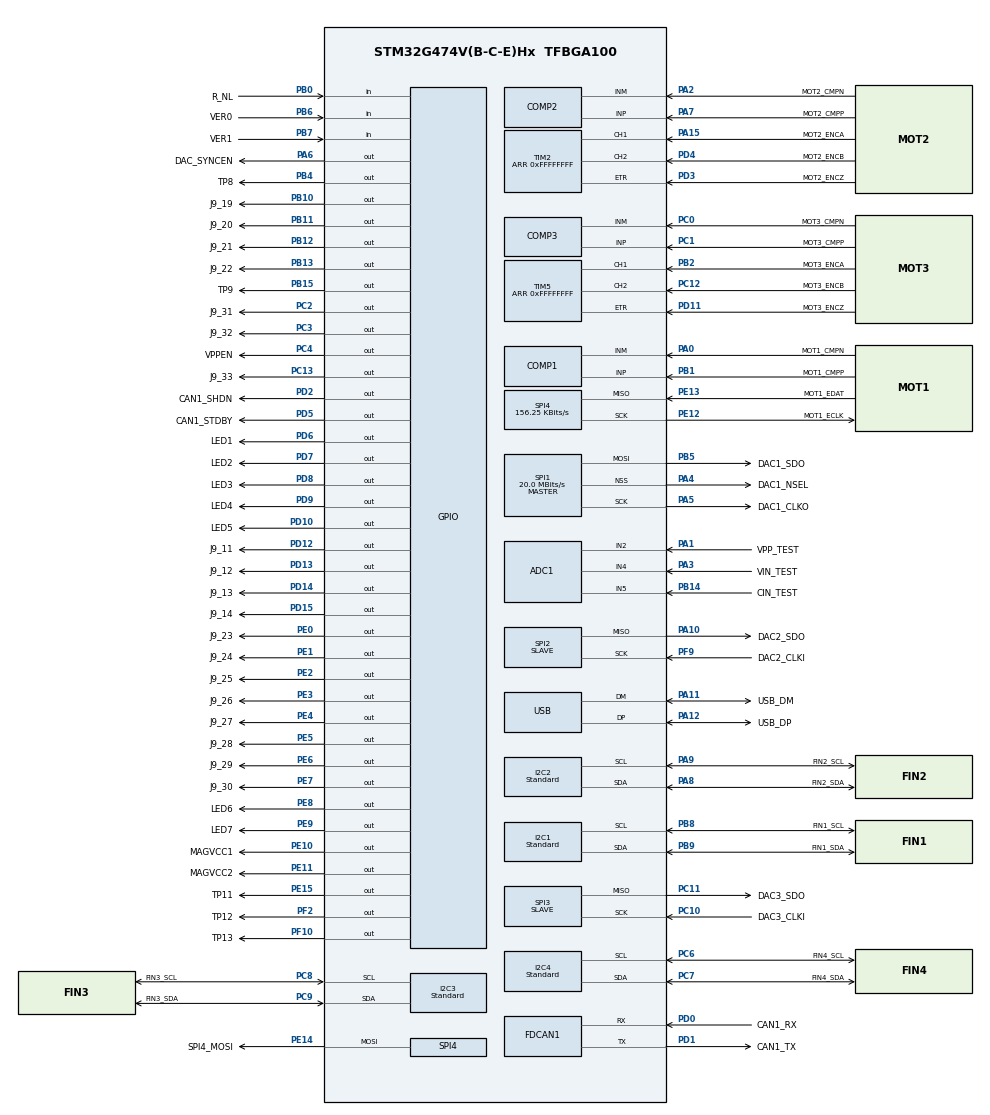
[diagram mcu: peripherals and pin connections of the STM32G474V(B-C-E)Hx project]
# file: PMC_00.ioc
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ADC1.Channel-1\#ChannelRegularConversion=ADC_CHANNEL_2
ADC1.Channel-10\#ChannelRegularConversion=ADC_CHANNEL_VBAT
ADC1.Channel-11\#ChannelRegularConversion=ADC_CHANNEL_VREFINT
ADC1.Channel-12\#ChannelRegularConversion=ADC_CHANNEL_VREFINT
ADC1.Channel-2\#ChannelRegularConversion=ADC_CHANNEL_2
ADC1.Channel-3\#ChannelRegularConversion=ADC_CHANNEL_4
ADC1.Channel-4\#ChannelRegularConversion=ADC_CHANNEL_4
ADC1.Channel-5\#ChannelRegularConversion=ADC_CHANNEL_5
ADC1.Channel-6\#ChannelRegularConversion=ADC_CHANNEL_5
ADC1.Channel-7\#ChannelRegularConversion=ADC_CHANNEL_TEMPSENSOR_ADC1
ADC1.Channel-8\#ChannelRegularConversion=ADC_CHANNEL_TEMPSENSOR_ADC1
ADC1.Channel-9\#ChannelRegularConversion=ADC_CHANNEL_VBAT
ADC1.ContinuousConvMode=DISABLE
ADC1.DMAContinuousRequests=ENABLE
ADC1.DiscontinuousConvMode=ENABLE
ADC1.EOCSelection=ADC_EOC_SEQ_CONV
ADC1.ExternalTrigConv=ADC_EXTERNALTRIG_T7_TRGO
ADC1.GainCompensation=4096
ADC1.NbrOfConversion=12
ADC1.NbrOfConversionFlag=1
ADC1.NbrOfDiscConversion=2
ADC1.OffsetNumber-1\#ChannelRegularConversion=ADC_OFFSET_NONE
ADC1.OffsetNumber-10\#ChannelRegularConversion=ADC_OFFSET_NONE
ADC1.OffsetNumber-11\#ChannelRegularConversion=ADC_OFFSET_NONE
ADC1.OffsetNumber-12\#ChannelRegularConversion=ADC_OFFSET_NONE
ADC1.OffsetNumber-2\#ChannelRegularConversion=ADC_OFFSET_NONE
ADC1.OffsetNumber-3\#ChannelRegularConversion=ADC_OFFSET_NONE
ADC1.OffsetNumber-4\#ChannelRegularConversion=ADC_OFFSET_NONE
ADC1.OffsetNumber-5\#ChannelRegularConversion=ADC_OFFSET_NONE
ADC1.OffsetNumber-6\#ChannelRegularConversion=ADC_OFFSET_NONE
ADC1.OffsetNumber-7\#ChannelRegularConversion=ADC_OFFSET_NONE
ADC1.OffsetNumber-8\#ChannelRegularConversion=ADC_OFFSET_NONE
ADC1.OffsetNumber-9\#ChannelRegularConversion=ADC_OFFSET_NONE
ADC1.Overrun=ADC_OVR_DATA_OVERWRITTEN
ADC1.Rank-1\#ChannelRegularConversion=1
ADC1.Rank-10\#ChannelRegularConversion=10
ADC1.Rank-11\#ChannelRegularConversion=11
ADC1.Rank-12\#ChannelRegularConversion=12
ADC1.Rank-2\#ChannelRegularConversion=2
ADC1.Rank-3\#ChannelRegularConversion=3
ADC1.Rank-4\#ChannelRegularConversion=4
ADC1.Rank-5\#ChannelRegularConversion=5
ADC1.Rank-6\#ChannelRegularConversion=6
ADC1.Rank-7\#ChannelRegularConversion=7
ADC1.Rank-8\#ChannelRegularConversion=8
ADC1.Rank-9\#ChannelRegularConversion=9
ADC1.SamplingTime-1\#ChannelRegularConversion=ADC_SAMPLETIME_640CYCLES_5
ADC1.SamplingTime-10\#ChannelRegularConversion=ADC_SAMPLETIME_640CYCLES_5
ADC1.SamplingTime-11\#ChannelRegularConversion=ADC_SAMPLETIME_640CYCLES_5
ADC1.SamplingTime-12\#ChannelRegularConversion=ADC_SAMPLETIME_640CYCLES_5
ADC1.SamplingTime-2\#ChannelRegularConversion=ADC_SAMPLETIME_640CYCLES_5
ADC1.SamplingTime-3\#ChannelRegularConversion=ADC_SAMPLETIME_640CYCLES_5
ADC1.SamplingTime-4\#ChannelRegularConversion=ADC_SAMPLETIME_640CYCLES_5
ADC1.SamplingTime-5\#ChannelRegularConversion=ADC_SAMPLETIME_640CYCLES_5
ADC1.SamplingTime-6\#ChannelRegularConversion=ADC_SAMPLETIME_640CYCLES_5
ADC1.SamplingTime-7\#ChannelRegularConversion=ADC_SAMPLETIME_640CYCLES_5
ADC1.SamplingTime-8\#ChannelRegularConversion=ADC_SAMPLETIME_640CYCLES_5
ADC1.SamplingTime-9\#ChannelRegularConversion=ADC_SAMPLETIME_640CYCLES_5
ADC1.master=1
COMP1.Hysteresis=COMP_HYSTERESIS_10MV
COMP1.TriggerMode=COMP_TRIGGERMODE_IT_RISING
COMP2.Hysteresis=COMP_HYSTERESIS_10MV
COMP2.TriggerMode=COMP_TRIGGERMODE_IT_RISING
COMP3.Hysteresis=COMP_HYSTERESIS_10MV
COMP3.TriggerMode=COMP_TRIGGERMODE_IT_RISING
Dma.ADC1.11.Direction=DMA_PERIPH_TO_MEMORY
Dma.ADC1.11.EventEnable=DISABLE
Dma.ADC1.11.Instance=DMA2_Channel4
Dma.ADC1.11.MemDataAlignment=DMA_MDATAALIGN_HALFWORD
Dma.ADC1.11.MemInc=DMA_MINC_ENABLE
Dma.ADC1.11.Mode=DMA_CIRCULAR
Dma.ADC1.11.PeriphDataAlignment=DMA_PDATAALIGN_HALFWORD
Dma.ADC1.11.PeriphInc=DMA_PINC_DISABLE
Dma.ADC1.11.Polarity=HAL_DMAMUX_REQ_GEN_RISING
Dma.ADC1.11.Priority=DMA_PRIORITY_HIGH
Dma.ADC1.11.RequestNumber=1
Dma.ADC1.11.SignalID=NONE
Dma.ADC1.11.SyncEnable=DISABLE
Dma.ADC1.11.SyncPolarity=HAL_DMAMUX_SYNC_NO_EVENT
Dma.ADC1.11.SyncRequestNumber=1
Dma.ADC1.11.SyncSignalID=NONE
Dma.I2C1_RX.3.Direction=DMA_PERIPH_TO_MEMORY
Dma.I2C1_RX.3.EventEnable=DISABLE
Dma.I2C1_RX.3.Instance=DMA1_Channel4
Dma.I2C1_RX.3.MemDataAlignment=DMA_MDATAALIGN_BYTE
Dma.I2C1_RX.3.MemInc=DMA_MINC_ENABLE
Dma.I2C1_RX.3.Mode=DMA_NORMAL
Dma.I2C1_RX.3.PeriphDataAlignment=DMA_PDATAALIGN_BYTE
Dma.I2C1_RX.3.PeriphInc=DMA_PINC_DISABLE
Dma.I2C1_RX.3.Polarity=HAL_DMAMUX_REQ_GEN_RISING
Dma.I2C1_RX.3.Priority=DMA_PRIORITY_MEDIUM
Dma.I2C1_RX.3.RequestNumber=1
Dma.I2C1_RX.3.SignalID=NONE
Dma.I2C1_RX.3.SyncEnable=DISABLE
Dma.I2C1_RX.3.SyncPolarity=HAL_DMAMUX_SYNC_NO_EVENT
Dma.I2C1_RX.3.SyncRequestNumber=1
Dma.I2C1_RX.3.SyncSignalID=NONE
Dma.I2C1_TX.4.Direction=DMA_MEMORY_TO_PERIPH
Dma.I2C1_TX.4.EventEnable=DISABLE
Dma.I2C1_TX.4.Instance=DMA1_Channel5
Dma.I2C1_TX.4.MemDataAlignment=DMA_MDATAALIGN_BYTE
Dma.I2C1_TX.4.MemInc=DMA_MINC_ENABLE
Dma.I2C1_TX.4.Mode=DMA_NORMAL
Dma.I2C1_TX.4.PeriphDataAlignment=DMA_PDATAALIGN_BYTE
Dma.I2C1_TX.4.PeriphInc=DMA_PINC_DISABLE
Dma.I2C1_TX.4.Polarity=HAL_DMAMUX_REQ_GEN_RISING
Dma.I2C1_TX.4.Priority=DMA_PRIORITY_LOW
Dma.I2C1_TX.4.RequestNumber=1
Dma.I2C1_TX.4.SignalID=NONE
Dma.I2C1_TX.4.SyncEnable=DISABLE
Dma.I2C1_TX.4.SyncPolarity=HAL_DMAMUX_SYNC_NO_EVENT
Dma.I2C1_TX.4.SyncRequestNumber=1
Dma.I2C1_TX.4.SyncSignalID=NONE
Dma.I2C2_RX.5.Direction=DMA_PERIPH_TO_MEMORY
Dma.I2C2_RX.5.EventEnable=DISABLE
Dma.I2C2_RX.5.Instance=DMA1_Channel6
Dma.I2C2_RX.5.MemDataAlignment=DMA_MDATAALIGN_BYTE
Dma.I2C2_RX.5.MemInc=DMA_MINC_ENABLE
Dma.I2C2_RX.5.Mode=DMA_NORMAL
Dma.I2C2_RX.5.PeriphDataAlignment=DMA_PDATAALIGN_BYTE
Dma.I2C2_RX.5.PeriphInc=DMA_PINC_DISABLE
Dma.I2C2_RX.5.Polarity=HAL_DMAMUX_REQ_GEN_RISING
Dma.I2C2_RX.5.Priority=DMA_PRIORITY_LOW
Dma.I2C2_RX.5.RequestNumber=1
Dma.I2C2_RX.5.SignalID=NONE
Dma.I2C2_RX.5.SyncEnable=DISABLE
Dma.I2C2_RX.5.SyncPolarity=HAL_DMAMUX_SYNC_NO_EVENT
Dma.I2C2_RX.5.SyncRequestNumber=1
Dma.I2C2_RX.5.SyncSignalID=NONE
Dma.I2C2_TX.6.Direction=DMA_MEMORY_TO_PERIPH
Dma.I2C2_TX.6.EventEnable=DISABLE
Dma.I2C2_TX.6.Instance=DMA1_Channel7
Dma.I2C2_TX.6.MemDataAlignment=DMA_MDATAALIGN_BYTE
Dma.I2C2_TX.6.MemInc=DMA_MINC_ENABLE
Dma.I2C2_TX.6.Mode=DMA_NORMAL
Dma.I2C2_TX.6.PeriphDataAlignment=DMA_PDATAALIGN_BYTE
Dma.I2C2_TX.6.PeriphInc=DMA_PINC_DISABLE
Dma.I2C2_TX.6.Polarity=HAL_DMAMUX_REQ_GEN_RISING
Dma.I2C2_TX.6.Priority=DMA_PRIORITY_MEDIUM
Dma.I2C2_TX.6.RequestNumber=1
Dma.I2C2_TX.6.SignalID=NONE
Dma.I2C2_TX.6.SyncEnable=DISABLE
Dma.I2C2_TX.6.SyncPolarity=HAL_DMAMUX_SYNC_NO_EVENT
Dma.I2C2_TX.6.SyncRequestNumber=1
Dma.I2C2_TX.6.SyncSignalID=NONE
Dma.I2C3_RX.7.Direction=DMA_PERIPH_TO_MEMORY
Dma.I2C3_RX.7.EventEnable=DISABLE
Dma.I2C3_RX.7.Instance=DMA1_Channel8
Dma.I2C3_RX.7.MemDataAlignment=DMA_MDATAALIGN_BYTE
Dma.I2C3_RX.7.MemInc=DMA_MINC_ENABLE
Dma.I2C3_RX.7.Mode=DMA_NORMAL
Dma.I2C3_RX.7.PeriphDataAlignment=DMA_PDATAALIGN_BYTE
Dma.I2C3_RX.7.PeriphInc=DMA_PINC_DISABLE
Dma.I2C3_RX.7.Polarity=HAL_DMAMUX_REQ_GEN_RISING
Dma.I2C3_RX.7.Priority=DMA_PRIORITY_LOW
Dma.I2C3_RX.7.RequestNumber=1
Dma.I2C3_RX.7.SignalID=NONE
Dma.I2C3_RX.7.SyncEnable=DISABLE
Dma.I2C3_RX.7.SyncPolarity=HAL_DMAMUX_SYNC_NO_EVENT
Dma.I2C3_RX.7.SyncRequestNumber=1
Dma.I2C3_RX.7.SyncSignalID=NONE
Dma.I2C3_TX.8.Direction=DMA_MEMORY_TO_PERIPH
Dma.I2C3_TX.8.EventEnable=DISABLE
Dma.I2C3_TX.8.Instance=DMA2_Channel1
Dma.I2C3_TX.8.MemDataAlignment=DMA_MDATAALIGN_BYTE
Dma.I2C3_TX.8.MemInc=DMA_MINC_ENABLE
Dma.I2C3_TX.8.Mode=DMA_NORMAL
Dma.I2C3_TX.8.PeriphDataAlignment=DMA_PDATAALIGN_BYTE
Dma.I2C3_TX.8.PeriphInc=DMA_PINC_DISABLE
Dma.I2C3_TX.8.Polarity=HAL_DMAMUX_REQ_GEN_RISING
Dma.I2C3_TX.8.Priority=DMA_PRIORITY_LOW
Dma.I2C3_TX.8.RequestNumber=1
Dma.I2C3_TX.8.SignalID=NONE
Dma.I2C3_TX.8.SyncEnable=DISABLE
Dma.I2C3_TX.8.SyncPolarity=HAL_DMAMUX_SYNC_NO_EVENT
Dma.I2C3_TX.8.SyncRequestNumber=1
Dma.I2C3_TX.8.SyncSignalID=NONE
Dma.I2C4_RX.9.Direction=DMA_PERIPH_TO_MEMORY
Dma.I2C4_RX.9.EventEnable=DISABLE
Dma.I2C4_RX.9.Instance=DMA2_Channel2
Dma.I2C4_RX.9.MemDataAlignment=DMA_MDATAALIGN_BYTE
Dma.I2C4_RX.9.MemInc=DMA_MINC_ENABLE
Dma.I2C4_RX.9.Mode=DMA_NORMAL
Dma.I2C4_RX.9.PeriphDataAlignment=DMA_PDATAALIGN_BYTE
Dma.I2C4_RX.9.PeriphInc=DMA_PINC_DISABLE
Dma.I2C4_RX.9.Polarity=HAL_DMAMUX_REQ_GEN_RISING
Dma.I2C4_RX.9.Priority=DMA_PRIORITY_MEDIUM
Dma.I2C4_RX.9.RequestNumber=1
Dma.I2C4_RX.9.SignalID=NONE
Dma.I2C4_RX.9.SyncEnable=DISABLE
Dma.I2C4_RX.9.SyncPolarity=HAL_DMAMUX_SYNC_NO_EVENT
Dma.I2C4_RX.9.SyncRequestNumber=1
Dma.I2C4_RX.9.SyncSignalID=NONE
Dma.I2C4_TX.10.Direction=DMA_MEMORY_TO_PERIPH
Dma.I2C4_TX.10.EventEnable=DISABLE
Dma.I2C4_TX.10.Instance=DMA2_Channel3
Dma.I2C4_TX.10.MemDataAlignment=DMA_MDATAALIGN_BYTE
Dma.I2C4_TX.10.MemInc=DMA_MINC_ENABLE
Dma.I2C4_TX.10.Mode=DMA_NORMAL
Dma.I2C4_TX.10.PeriphDataAlignment=DMA_PDATAALIGN_BYTE
Dma.I2C4_TX.10.PeriphInc=DMA_PINC_DISABLE
Dma.I2C4_TX.10.Polarity=HAL_DMAMUX_REQ_GEN_RISING
Dma.I2C4_TX.10.Priority=DMA_PRIORITY_MEDIUM
Dma.I2C4_TX.10.RequestNumber=1
Dma.I2C4_TX.10.SignalID=NONE
Dma.I2C4_TX.10.SyncEnable=DISABLE
Dma.I2C4_TX.10.SyncPolarity=HAL_DMAMUX_SYNC_NO_EVENT
Dma.I2C4_TX.10.SyncRequestNumber=1
Dma.I2C4_TX.10.SyncSignalID=NONE
Dma.Request0=SPI1_TX
Dma.Request1=SPI2_TX
Dma.Request10=I2C4_TX
Dma.Request11=ADC1
Dma.Request2=SPI3_TX
Dma.Request3=I2C1_RX
Dma.Request4=I2C1_TX
Dma.Request5=I2C2_RX
Dma.Request6=I2C2_TX
Dma.Request7=I2C3_RX
Dma.Request8=I2C3_TX
Dma.Request9=I2C4_RX
Dma.SPI1_TX.0.Direction=DMA_MEMORY_TO_PERIPH
Dma.SPI1_TX.0.EventEnable=DISABLE
Dma.SPI1_TX.0.Instance=DMA1_Channel1
Dma.SPI1_TX.0.MemDataAlignment=DMA_MDATAALIGN_HALFWORD
Dma.SPI1_TX.0.MemInc=DMA_MINC_ENABLE
Dma.SPI1_TX.0.Mode=DMA_CIRCULAR
Dma.SPI1_TX.0.PeriphDataAlignment=DMA_PDATAALIGN_HALFWORD
Dma.SPI1_TX.0.PeriphInc=DMA_PINC_DISABLE
Dma.SPI1_TX.0.Polarity=HAL_DMAMUX_REQ_GEN_RISING
Dma.SPI1_TX.0.Priority=DMA_PRIORITY_HIGH
Dma.SPI1_TX.0.RequestNumber=1
Dma.SPI1_TX.0.SignalID=NONE
Dma.SPI1_TX.0.SyncEnable=DISABLE
Dma.SPI1_TX.0.SyncPolarity=HAL_DMAMUX_SYNC_NO_EVENT
Dma.SPI1_TX.0.SyncRequestNumber=1
Dma.SPI1_TX.0.SyncSignalID=NONE
Dma.SPI2_TX.1.Direction=DMA_MEMORY_TO_PERIPH
Dma.SPI2_TX.1.EventEnable=DISABLE
Dma.SPI2_TX.1.Instance=DMA1_Channel2
Dma.SPI2_TX.1.MemDataAlignment=DMA_MDATAALIGN_HALFWORD
Dma.SPI2_TX.1.MemInc=DMA_MINC_ENABLE
Dma.SPI2_TX.1.Mode=DMA_CIRCULAR
Dma.SPI2_TX.1.PeriphDataAlignment=DMA_PDATAALIGN_HALFWORD
Dma.SPI2_TX.1.PeriphInc=DMA_PINC_DISABLE
Dma.SPI2_TX.1.Polarity=HAL_DMAMUX_REQ_GEN_RISING
Dma.SPI2_TX.1.Priority=DMA_PRIORITY_VERY_HIGH
Dma.SPI2_TX.1.RequestNumber=1
Dma.SPI2_TX.1.SignalID=NONE
Dma.SPI2_TX.1.SyncEnable=DISABLE
Dma.SPI2_TX.1.SyncPolarity=HAL_DMAMUX_SYNC_NO_EVENT
Dma.SPI2_TX.1.SyncRequestNumber=1
Dma.SPI2_TX.1.SyncSignalID=NONE
Dma.SPI3_TX.2.Direction=DMA_MEMORY_TO_PERIPH
Dma.SPI3_TX.2.EventEnable=DISABLE
Dma.SPI3_TX.2.Instance=DMA1_Channel3
Dma.SPI3_TX.2.MemDataAlignment=DMA_MDATAALIGN_HALFWORD
Dma.SPI3_TX.2.MemInc=DMA_MINC_ENABLE
Dma.SPI3_TX.2.Mode=DMA_CIRCULAR
Dma.SPI3_TX.2.PeriphDataAlignment=DMA_PDATAALIGN_HALFWORD
Dma.SPI3_TX.2.PeriphInc=DMA_PINC_DISABLE
Dma.SPI3_TX.2.Polarity=HAL_DMAMUX_REQ_GEN_RISING
Dma.SPI3_TX.2.Priority=DMA_PRIORITY_VERY_HIGH
Dma.SPI3_TX.2.RequestNumber=1
Dma.SPI3_TX.2.SignalID=NONE
Dma.SPI3_TX.2.SyncEnable=DISABLE
Dma.SPI3_TX.2.SyncPolarity=HAL_DMAMUX_SYNC_NO_EVENT
Dma.SPI3_TX.2.SyncRequestNumber=1
Dma.SPI3_TX.2.SyncSignalID=NONE
FDCAN1.AutoRetransmission=ENABLE
FDCAN1.ClockDivider=FDCAN_CLOCK_DIV2
FDCAN1.DataPrescaler=1
FDCAN1.DataSyncJumpWidth=4
FDCAN1.DataTimeSeg1=5
FDCAN1.DataTimeSeg2=4
FDCAN1.FrameFormat=FDCAN_FRAME_FD_BRS
FDCAN1.NominalPrescaler=1
FDCAN1.NominalSyncJumpWidth=16
FDCAN1.NominalTimeSeg1=63
FDCAN1.NominalTimeSeg2=16
FDCAN1.ProtocolException=DISABLE
FDCAN1.StdFiltersNbr=1
FDCAN1.TransmitPause=ENABLE
I2C1.I2C_Speed_Mode=I2C_Standard
I2C1.Timing=0x30909DEC
I2C2.I2C_Speed_Mode=I2C_Standard
I2C2.Timing=0x30909DEC
I2C3.I2C_Speed_Mode=I2C_Standard
I2C3.Timing=0x30909DEC
I2C4.I2C_Speed_Mode=I2C_Standard
I2C4.Timing=0x30909DEC
Mcu.Family=STM32G4
Mcu.Name=STM32G474V(B-C-E)Hx
Mcu.Package=TFBGA100
NVIC.ADC1_2_IRQn=true\:0\:0\:false\:false\:true\:true\:true
NVIC.COMP1_2_3_IRQn=true\:0\:0\:false\:false\:true\:false\:true
NVIC.DMA1_Channel1_IRQn=true\:0\:0\:false\:false\:true\:false\:true
NVIC.DMA1_Channel2_IRQn=true\:0\:0\:false\:false\:true\:false\:true
NVIC.DMA1_Channel3_IRQn=true\:0\:0\:false\:false\:true\:false\:true
NVIC.DMA1_Channel4_IRQn=true\:0\:0\:false\:false\:true\:false\:true
NVIC.DMA1_Channel5_IRQn=true\:0\:0\:false\:false\:true\:false\:true
NVIC.DMA1_Channel6_IRQn=true\:0\:0\:false\:false\:true\:false\:true
NVIC.DMA1_Channel7_IRQn=true\:0\:0\:false\:false\:true\:false\:true
NVIC.DMA1_Channel8_IRQn=true\:0\:0\:false\:false\:true\:false\:true
NVIC.DMA2_Channel1_IRQn=true\:0\:0\:false\:false\:true\:false\:true
NVIC.DMA2_Channel2_IRQn=true\:0\:0\:false\:false\:true\:false\:true
NVIC.DMA2_Channel3_IRQn=true\:0\:0\:false\:false\:true\:false\:true
NVIC.DMA2_Channel4_IRQn=true\:0\:0\:false\:false\:true\:false\:true
NVIC.FDCAN1_IT0_IRQn=true\:0\:0\:false\:false\:true\:true\:true
NVIC.FDCAN1_IT1_IRQn=true\:0\:0\:false\:false\:true\:true\:true
NVIC.I2C1_ER_IRQn=true\:0\:0\:false\:false\:true\:true\:true
NVIC.I2C1_EV_IRQn=true\:0\:0\:false\:false\:true\:true\:true
NVIC.I2C2_ER_IRQn=true\:0\:0\:false\:false\:true\:true\:true
NVIC.I2C2_EV_IRQn=true\:0\:0\:false\:false\:true\:true\:true
NVIC.I2C3_ER_IRQn=true\:0\:0\:false\:false\:true\:true\:true
NVIC.I2C3_EV_IRQn=true\:0\:0\:false\:false\:true\:true\:true
NVIC.I2C4_ER_IRQn=true\:0\:0\:false\:false\:true\:true\:true
NVIC.I2C4_EV_IRQn=true\:0\:0\:false\:false\:true\:true\:true
NVIC.PriorityGroup=NVIC_PRIORITYGROUP_4
NVIC.SPI1_IRQn=true\:0\:0\:false\:false\:true\:true\:true
NVIC.SPI2_IRQn=true\:0\:0\:false\:false\:true\:true\:true
NVIC.SPI3_IRQn=true\:0\:0\:false\:false\:true\:true\:true
NVIC.SPI4_IRQn=true\:0\:0\:false\:false\:true\:true\:true
NVIC.TIM2_IRQn=true\:0\:0\:false\:false\:true\:true\:true
NVIC.TIM5_IRQn=true\:0\:0\:false\:false\:true\:true\:true
PA0.GPIO_Label=MOT1_CMPN
PA0.Mode=INM
PA0.Signal=COMP1_INM
PA1.GPIO_Label=VPP_TEST
PA1.Mode=IN2-Single-Ended
PA1.Signal=ADC1_IN2
PA10.GPIO_Label=DAC2_SDO
PA10.GPIO_PuPd=GPIO_PULLUP
PA10.GPIO_Speed=GPIO_SPEED_FREQ_VERY_HIGH
PA10.Mode=TX_Only_Simplex_Unidirect_Slave
PA10.Signal=SPI2_MISO
PA11.GPIO_Label=USB_DM
PA11.Mode=Device
PA11.Signal=USB_DM
PA12.GPIO_Label=USB_DP
PA12.Mode=Device
PA12.Signal=USB_DP
PA13.GPIO_Label=SWDIO
PA13.Mode=Trace_Asynchronous_SW
PA13.Signal=SYS_JTMS-SWDIO
PA14.GPIO_Label=SWCLK
PA14.Mode=Trace_Asynchronous_SW
PA14.Signal=SYS_JTCK-SWCLK
PA15.GPIO_Label=MOT2_ENCA
PA15.GPIO_Speed=GPIO_SPEED_FREQ_VERY_HIGH
PA15.Signal=S_TIM2_CH1
PA2.GPIO_Label=MOT2_CMPN
PA2.Mode=INM
PA2.Signal=COMP2_INM
PA3.GPIO_Label=VIN_TEST
PA3.Mode=IN4-Single-Ended
PA3.Signal=ADC1_IN4
PA4.GPIO_Label=DAC1_NSEL
PA4.GPIO_PuPd=GPIO_PULLUP
PA4.GPIO_Speed=GPIO_SPEED_FREQ_VERY_HIGH
PA4.Mode=NSS_Signal_Hard_Output
PA4.Signal=SPI1_NSS
PA5.GPIO_Label=DAC1_CLKO
PA5.GPIO_PuPd=GPIO_PULLUP
PA5.GPIO_Speed=GPIO_SPEED_FREQ_VERY_HIGH
PA5.Mode=TX_Only_Simplex_Unidirect_Master
PA5.Signal=SPI1_SCK
PA6.GPIO_Label=DAC_SYNCEN
PA6.GPIO_Speed=GPIO_SPEED_FREQ_HIGH
PA6.Signal=GPIO_Output
PA7.GPIO_Label=MOT2_CMPP
PA7.Mode=INP
PA7.Signal=COMP2_INP
PA8.GPIO_Label=FIN2_SDA
PA8.GPIO_Speed=GPIO_SPEED_FREQ_VERY_HIGH
PA8.Mode=I2C
PA8.Signal=I2C2_SDA
PA9.GPIO_Label=FIN2_SCL
PA9.GPIO_Speed=GPIO_SPEED_FREQ_VERY_HIGH
PA9.Mode=I2C
PA9.Signal=I2C2_SCL
PB0.GPIO_Label=R_NL
PB0.Signal=GPIO_Input
PB1.GPIO_Label=MOT1_CMPP
PB1.Mode=INP
PB1.Signal=COMP1_INP
PB10.GPIO_Label=J9_19
PB10.Signal=GPIO_Output
PB11.GPIO_Label=J9_20
PB11.Signal=GPIO_Output
PB12.GPIO_Label=J9_21
PB12.Signal=GPIO_Output
PB13.GPIO_Label=J9_22
PB13.Signal=GPIO_Output
PB14.GPIO_Label=CIN_TEST
PB14.Mode=IN5-Single-Ended
PB14.Signal=ADC1_IN5
PB15.GPIO_Label=TP9
PB15.Signal=GPIO_Output
PB2.GPIO_Label=MOT3_ENCA
PB2.GPIO_Speed=GPIO_SPEED_FREQ_VERY_HIGH
PB2.Signal=S_TIM5_CH1
PB3.GPIO_Label=SWO
PB3.Mode=Trace_Asynchronous_SW
PB3.Signal=SYS_JTDO-SWO
PB4.GPIO_Label=TP8
PB4.Signal=GPIO_Output
PB5.GPIO_Label=DAC1_SDO
PB5.GPIO_PuPd=GPIO_PULLUP
PB5.GPIO_Speed=GPIO_SPEED_FREQ_VERY_HIGH
PB5.Mode=TX_Only_Simplex_Unidirect_Master
PB5.Signal=SPI1_MOSI
PB6.GPIO_Label=VER0
PB6.Signal=GPIO_Input
PB7.GPIO_Label=VER1
PB7.Signal=GPIO_Input
PB8-BOOT0.GPIO_FM8=__NULL
PB8-BOOT0.GPIO_Label=FIN1_SCL
PB8-BOOT0.GPIO_Speed=GPIO_SPEED_FREQ_VERY_HIGH
PB8-BOOT0.Mode=I2C
PB8-BOOT0.Signal=I2C1_SCL
PB9.GPIO_FM9=__NULL
PB9.GPIO_Label=FIN1_SDA
PB9.GPIO_Speed=GPIO_SPEED_FREQ_VERY_HIGH
PB9.Mode=I2C
PB9.Signal=I2C1_SDA
PC0.GPIO_Label=MOT3_CMPN
PC0.Mode=INM
PC0.Signal=COMP3_INM
PC1.GPIO_Label=MOT3_CMPP
PC1.Mode=INP
PC1.Signal=COMP3_INP
PC10.GPIO_Label=DAC3_CLKI
PC10.GPIO_Speed=GPIO_SPEED_FREQ_VERY_HIGH
PC10.Mode=TX_Only_Simplex_Unidirect_Slave
PC10.Signal=SPI3_SCK
PC11.GPIO_Label=DAC3_SDO
PC11.GPIO_PuPd=GPIO_PULLUP
PC11.GPIO_Speed=GPIO_SPEED_FREQ_VERY_HIGH
PC11.Mode=TX_Only_Simplex_Unidirect_Slave
PC11.Signal=SPI3_MISO
PC12.GPIO_Label=MOT3_ENCB
PC12.GPIO_Speed=GPIO_SPEED_FREQ_VERY_HIGH
PC12.Signal=S_TIM5_CH2
PC13.GPIO_Label=J9_33
PC13.Signal=GPIO_Output
PC14-OSC32_IN.GPIO_Label=OSC32_IN
PC14-OSC32_IN.Mode=LSE-External-Oscillator
PC14-OSC32_IN.Signal=RCC_OSC32_IN
PC15-OSC32_OUT.GPIO_Label=OSC32_OUT
PC15-OSC32_OUT.Mode=LSE-External-Oscillator
PC15-OSC32_OUT.Signal=RCC_OSC32_OUT
PC2.GPIO_Label=J9_31
PC2.Signal=GPIO_Output
PC3.GPIO_Label=J9_32
PC3.Signal=GPIO_Output
PC4.GPIO_Label=VPPEN
PC4.GPIO_Speed=GPIO_SPEED_FREQ_HIGH
PC4.Signal=GPIO_Output
PC5.GPIO_Label=NPWF
PC5.Mode=SYS_WakeUp4
PC5.Signal=SYS_WKUP5
PC6.GPIO_Label=FIN4_SCL
PC6.GPIO_Speed=GPIO_SPEED_FREQ_VERY_HIGH
PC6.Mode=I2C
PC6.Signal=I2C4_SCL
PC7.GPIO_Label=FIN4_SDA
PC7.GPIO_Speed=GPIO_SPEED_FREQ_VERY_HIGH
PC7.Mode=I2C
PC7.Signal=I2C4_SDA
PC8.GPIO_Label=FIN3_SCL
PC8.GPIO_Speed=GPIO_SPEED_FREQ_VERY_HIGH
PC8.Mode=I2C
PC8.Signal=I2C3_SCL
PC9.GPIO_Label=FIN3_SDA
PC9.GPIO_Speed=GPIO_SPEED_FREQ_VERY_HIGH
PC9.Mode=I2C
PC9.Signal=I2C3_SDA
PD0.GPIO_Label=CAN1_RX
PD0.GPIO_Speed=GPIO_SPEED_FREQ_VERY_HIGH
PD0.Mode=FDCAN_Activate
PD0.Signal=FDCAN1_RX
PD1.GPIO_Label=CAN1_TX
PD1.GPIO_Speed=GPIO_SPEED_FREQ_VERY_HIGH
PD1.Mode=FDCAN_Activate
PD1.Signal=FDCAN1_TX
PD10.GPIO_Label=LED5
PD10.GPIO_Speed=GPIO_SPEED_FREQ_HIGH
PD10.PinState=GPIO_PIN_SET
PD10.Signal=GPIO_Output
PD11.GPIO_Label=MOT3_ENCZ
PD11.GPIO_Speed=GPIO_SPEED_FREQ_VERY_HIGH
PD11.Signal=S_TIM5_ETR
PD12.GPIO_Label=J9_11
PD12.Signal=GPIO_Output
PD13.GPIO_Label=J9_12
PD13.Signal=GPIO_Output
PD14.GPIO_Label=J9_13
PD14.Signal=GPIO_Output
PD15.GPIO_Label=J9_14
PD15.Signal=GPIO_Output
PD2.GPIO_Label=CAN1_SHDN
PD2.GPIO_Speed=GPIO_SPEED_FREQ_HIGH
PD2.PinState=GPIO_PIN_SET
PD2.Signal=GPIO_Output
PD3.GPIO_Label=MOT2_ENCZ
PD3.GPIO_Speed=GPIO_SPEED_FREQ_VERY_HIGH
PD3.Signal=S_TIM2_ETR
PD4.GPIO_Label=MOT2_ENCB
PD4.GPIO_Speed=GPIO_SPEED_FREQ_VERY_HIGH
PD4.Signal=S_TIM2_CH2
PD5.GPIO_Label=CAN1_STDBY
PD5.GPIO_Speed=GPIO_SPEED_FREQ_HIGH
PD5.PinState=GPIO_PIN_SET
PD5.Signal=GPIO_Output
PD6.GPIO_Label=LED1
PD6.GPIO_Speed=GPIO_SPEED_FREQ_HIGH
PD6.PinState=GPIO_PIN_RESET
PD6.Signal=GPIO_Output
PD7.GPIO_Label=LED2
PD7.GPIO_Speed=GPIO_SPEED_FREQ_HIGH
PD7.Signal=GPIO_Output
PD8.GPIO_Label=LED3
PD8.GPIO_Speed=GPIO_SPEED_FREQ_HIGH
PD8.Signal=GPIO_Output
PD9.GPIO_Label=LED4
PD9.GPIO_Speed=GPIO_SPEED_FREQ_HIGH
PD9.PinState=GPIO_PIN_SET
PD9.Signal=GPIO_Output
PE0.GPIO_Label=J9_23
PE0.Signal=GPIO_Output
PE1.GPIO_Label=J9_24
PE1.Signal=GPIO_Output
PE10.GPIO_Label=MAGVCC1
PE10.GPIO_Speed=GPIO_SPEED_FREQ_HIGH
PE10.Signal=GPIO_Output
PE11.GPIO_Label=MAGVCC2
PE11.GPIO_Speed=GPIO_SPEED_FREQ_HIGH
PE11.Signal=GPIO_Output
PE12.GPIO_Label=MOT1_ECLK
PE12.GPIO_Speed=GPIO_SPEED_FREQ_VERY_HIGH
PE12.Mode=Full_Duplex_Master
PE12.Signal=SPI4_SCK
PE13.GPIO_Label=MOT1_EDAT
PE13.GPIO_Speed=GPIO_SPEED_FREQ_VERY_HIGH
PE13.Mode=Full_Duplex_Master
PE13.Signal=SPI4_MISO
PE14.GPIO_Label=SPI4_MOSI
PE14.GPIO_Speed=GPIO_SPEED_FREQ_VERY_HIGH
PE14.Mode=Full_Duplex_Master
PE14.Signal=SPI4_MOSI
PE15.GPIO_Label=TP11
PE15.Signal=GPIO_Output
PE2.GPIO_Label=J9_25
PE2.Signal=GPIO_Output
PE3.GPIO_Label=J9_26
PE3.Signal=GPIO_Output
PE4.GPIO_Label=J9_27
PE4.Signal=GPIO_Output
PE5.GPIO_Label=J9_28
PE5.Signal=GPIO_Output
PE6.GPIO_Label=J9_29
PE6.Signal=GPIO_Output
PE7.GPIO_Label=J9_30
PE7.Signal=GPIO_Output
PE8.GPIO_Label=LED6
PE8.GPIO_Speed=GPIO_SPEED_FREQ_HIGH
PE8.PinState=GPIO_PIN_SET
PE8.Signal=GPIO_Output
PE9.GPIO_Label=LED7
PE9.GPIO_Speed=GPIO_SPEED_FREQ_HIGH
PE9.PinState=GPIO_PIN_SET
PE9.Signal=GPIO_Output
PF0-OSC_IN.GPIO_Label=OSC_IN
PF0-OSC_IN.Mode=HSE-External-Oscillator
PF0-OSC_IN.Signal=RCC_OSC_IN
PF1-OSC_OUT.GPIO_Label=OSC_OUT
PF1-OSC_OUT.Mode=HSE-External-Oscillator
PF1-OSC_OUT.Signal=RCC_OSC_OUT
PF10.GPIO_Label=TP13
PF10.Signal=GPIO_Output
PF2.GPIO_Label=TP12
PF2.Signal=GPIO_Output
PF9.GPIO_Label=DAC2_CLKI
PF9.GPIO_Speed=GPIO_SPEED_FREQ_VERY_HIGH
PF9.Mode=TX_Only_Simplex_Unidirect_Slave
PF9.Signal=SPI2_SCK
ProjectManager.HeapSize=0x800
ProjectManager.StackSize=0x800
ProjectManager.TargetToolchain=MDK-ARM V5.27
RCC.ADC12Freq_Value=160000000
RCC.ADC345Freq_Value=160000000
RCC.AHBFreq_Value=160000000
RCC.APB1Freq_Value=160000000
RCC.APB1TimFreq_Value=160000000
RCC.APB2CLKDivider=RCC_HCLK_DIV4
RCC.APB2Freq_Value=40000000
RCC.APB2TimFreq_Value=80000000
RCC.CK48CLockSelection=RCC_USBCLKSOURCE_HSI48
RCC.CortexFreq_Value=160000000
RCC.EXTERNAL_CLOCK_VALUE=12288000
RCC.HCLKFreq_Value=160000000
RCC.HSE_VALUE=16000000
RCC.HSI48_VALUE=48000000
RCC.HSI_VALUE=16000000
RCC.PLLM=RCC_PLLM_DIV2
RCC.PLLN=40
RCC.PLLQ=RCC_PLLQ_DIV8
RCC.PLLSourceVirtual=RCC_PLLSOURCE_HSE
RCC.RTCClockSelection=RCC_RTCCLKSOURCE_LSE
RCC.SYSCLKFreq_VALUE=160000000
RCC.SYSCLKSource=RCC_SYSCLKSOURCE_PLLCLK
RCC.USBFreq_Value=48000000
RCC.VCOOutputFreq_Value=320000000
RTC.Alarm-Alarm\ A=RTC_ALARM_A
RTC.Alarm_B-Alarm\ B=RTC_ALARM_B
SH.S_TIM2_CH1.0=TIM2_CH1,Encoder_Interface_w_index
SH.S_TIM2_CH2.0=TIM2_CH2,Encoder_Interface_w_index
SH.S_TIM2_ETR.0=TIM2_ETR,Encoder_Interface_w_index
SH.S_TIM5_CH1.0=TIM5_CH1,Encoder_Interface_w_index
SH.S_TIM5_CH2.0=TIM5_CH2,Encoder_Interface_w_index
SH.S_TIM5_ETR.0=TIM5_ETR,Encoder_Interface_w_index
SPI1.BaudRatePrescaler=SPI_BAUDRATEPRESCALER_2
SPI1.CLKPolarity=SPI_POLARITY_HIGH
SPI1.CalculateBaudRate=20.0 MBits/s
SPI1.DataSize=SPI_DATASIZE_16BIT
SPI1.Direction=SPI_DIRECTION_2LINES
SPI1.Mode=SPI_MODE_MASTER
SPI1.VirtualNSS=VM_NSSHARD
SPI1.VirtualType=VM_MASTER
SPI2.CLKPolarity=SPI_POLARITY_HIGH
SPI2.DataSize=SPI_DATASIZE_16BIT
SPI2.Direction=SPI_DIRECTION_2LINES
SPI2.Mode=SPI_MODE_SLAVE
SPI2.VirtualType=VM_SLAVE
SPI3.CLKPolarity=SPI_POLARITY_HIGH
SPI3.DataSize=SPI_DATASIZE_16BIT
SPI3.Direction=SPI_DIRECTION_2LINES
SPI3.Mode=SPI_MODE_SLAVE
SPI3.VirtualType=VM_SLAVE
SPI4.BaudRatePrescaler=SPI_BAUDRATEPRESCALER_256
SPI4.CLKPolarity=SPI_POLARITY_HIGH
SPI4.CalculateBaudRate=156.25 KBits/s
SPI4.DataSize=SPI_DATASIZE_16BIT
SPI4.Direction=SPI_DIRECTION_2LINES
SPI4.Mode=SPI_MODE_MASTER
SPI4.NSSPMode=SPI_NSS_PULSE_DISABLE
SPI4.VirtualType=VM_MASTER
SYS.VoltageScaling=SYSCFG_VREFBUF_VOLTAGE_SCALE1
TIM2.EncoderMode=TIM_ENCODERMODE_TI12
TIM2.IndexPosition=TIM_ENCODERINDEX_POSITION_11
TIM2.PeriodNoDither=0xFFFFFFFF
TIM5.EncoderMode=TIM_ENCODERMODE_TI12
TIM5.IndexPosition=TIM_ENCODERINDEX_POSITION_11
TIM5.PeriodNoDither=0xFFFFFFFF
TIM7.PeriodNoDither=4999
TIM7.Prescaler=83
TIM7.TIM_MasterOutputTrigger=TIM_TRGO_UPDATE
VP_ADC1_TempSens_Input.Mode=IN-TempSens
VP_ADC1_Vbat_Input.Mode=IN-Vbat
VP_ADC1_Vref_Input.Mode=IN-Vrefint
VP_CORDIC_VS_CORDIC.Mode=CORDIC_Activate
VP_CRC_VS_CRC.Mode=CRC_Activate
VP_FMAC_VS_FMAC.Mode=FMAC_Activate
VP_RNG_VS_RNG.Mode=RNG_Activate
VP_RTC_VS_RTC_Activate.Mode=RTC_Enabled
VP_RTC_VS_RTC_Alarm_A_Intern.Mode=Alarm A
VP_RTC_VS_RTC_Alarm_B_Intern.Mode=Alarm B
VP_RTC_VS_RTC_Calendar.Mode=RTC_Calendar
VP_RTC_VS_RTC_WakeUp_intern.Mode=WakeUp
VP_SYS_VS_DBSignals.Mode=DisableDeadBatterySignals
VP_TIM7_VS_ClockSourceINT.Mode=Enable_Timer
VREF+.GPIO_Label=VREF
VREF+.Mode=InternalMode
VREF+.Signal=VREFBUF_OUT
board=custom

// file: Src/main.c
/* USER CODE BEGIN Header */
/**
  ******************************************************************************
  * @file           : main.c
  * @brief          : Main program body
  ******************************************************************************
  * @attention
  *
  * <h2><center>&copy; Copyright (c) 2020 STMicroelectronics.
  * All rights reserved.</center></h2>
  *
  * This software component is licensed by ST under BSD 3-Clause license,
  * the "License"; You may not use this file except in compliance with the
  * License. You may obtain a copy of the License at:
  *                        opensource.org/licenses/BSD-3-Clause
  *
  ******************************************************************************
  */
/* USER CODE END Header */
#include "main.h"
#include "adc.h"
#include "comp.h"
#include "cordic.h"
#include "crc.h"
#include "dma.h"
#include "fdcan.h"
#include "fmac.h"
#include "i2c.h"
#include "rng.h"
#include "rtc.h"
#include "spi.h"
#include "tim.h"
#include "usb.h"
#include "gpio.h"

#define TEST_TLV

#if defined(TEST_TLV)
#include "test_tlv.h"
#endif

void SystemClock_Config(void);

int main(void)
{

  /* MCU Configuration--------------------------------------------------------*/

  /* Reset of all peripherals, Initializes the Flash interface and the Systick. */
  HAL_Init();

  /* Configure the system clock */
  SystemClock_Config();

#if defined(TEST_TLV)

    //test_tlv_changeoftheaddress();
    test_tlv_init();
    for(;;);

#else
  /* Initialize all configured peripherals */
  MX_GPIO_Init();
  MX_DMA_Init();
  MX_ADC1_Init();
  MX_COMP1_Init();
  MX_COMP2_Init();
  MX_COMP3_Init();
  MX_CORDIC_Init();
  MX_CRC_Init();
  MX_FDCAN1_Init();
  MX_FMAC_Init();
  MX_I2C1_Init();
  MX_I2C2_Init();
  MX_I2C3_Init();
  MX_I2C4_Init();
  MX_RNG_Init();
  MX_RTC_Init();
  MX_SPI1_Init();
  MX_SPI2_Init();
  MX_SPI3_Init();
  MX_SPI4_Init();
  MX_TIM2_Init();
  MX_TIM5_Init();
  MX_TIM7_Init();
  MX_USB_PCD_Init();

  /* Infinite loop */
  while (1)
  {

  }

  #endif
}

void SystemClock_Config(void)
{
  RCC_OscInitTypeDef RCC_OscInitStruct = {0};
  RCC_ClkInitTypeDef RCC_ClkInitStruct = {0};
  RCC_PeriphCLKInitTypeDef PeriphClkInit = {0};

  /** Configure the main internal regulator output voltage
  */
  HAL_PWREx_ControlVoltageScaling(PWR_REGULATOR_VOLTAGE_SCALE1_BOOST);
  /** Configure LSE Drive Capability
  */
  HAL_PWR_EnableBkUpAccess();
  __HAL_RCC_LSEDRIVE_CONFIG(RCC_LSEDRIVE_LOW);
  /** Initializes the RCC Oscillators according to the specified parameters
  * in the RCC_OscInitTypeDef structure.
  */
  RCC_OscInitStruct.OscillatorType = RCC_OSCILLATORTYPE_HSI48|RCC_OSCILLATORTYPE_HSE
                              |RCC_OSCILLATORTYPE_LSE;
  RCC_OscInitStruct.HSEState = RCC_HSE_ON;
  RCC_OscInitStruct.LSEState = RCC_LSE_ON;
  RCC_OscInitStruct.HSI48State = RCC_HSI48_ON;
  RCC_OscInitStruct.PLL.PLLState = RCC_PLL_ON;
  RCC_OscInitStruct.PLL.PLLSource = RCC_PLLSOURCE_HSE;
  RCC_OscInitStruct.PLL.PLLM = RCC_PLLM_DIV2;
  RCC_OscInitStruct.PLL.PLLN = 40;
  RCC_OscInitStruct.PLL.PLLP = RCC_PLLP_DIV2;
  RCC_OscInitStruct.PLL.PLLQ = RCC_PLLQ_DIV8;
  RCC_OscInitStruct.PLL.PLLR = RCC_PLLR_DIV2;
  if (HAL_RCC_OscConfig(&RCC_OscInitStruct) != HAL_OK)
  {
    Error_Handler();
  }
  /** Initializes the CPU, AHB and APB buses clocks
  */
  RCC_ClkInitStruct.ClockType = RCC_CLOCKTYPE_HCLK|RCC_CLOCKTYPE_SYSCLK
                              |RCC_CLOCKTYPE_PCLK1|RCC_CLOCKTYPE_PCLK2;
  RCC_ClkInitStruct.SYSCLKSource = RCC_SYSCLKSOURCE_PLLCLK;
  RCC_ClkInitStruct.AHBCLKDivider = RCC_SYSCLK_DIV1;
  RCC_ClkInitStruct.APB1CLKDivider = RCC_HCLK_DIV2;
  RCC_ClkInitStruct.APB2CLKDivider = RCC_HCLK_DIV4;

  if (HAL_RCC_ClockConfig(&RCC_ClkInitStruct, FLASH_LATENCY_4) != HAL_OK)
  {
    Error_Handler();
  }
  /** Initializes the peripherals clocks
  */
  PeriphClkInit.PeriphClockSelection = RCC_PERIPHCLK_RTC|RCC_PERIPHCLK_I2C1
                              |RCC_PERIPHCLK_I2C2|RCC_PERIPHCLK_I2C3
                              |RCC_PERIPHCLK_I2C4|RCC_PERIPHCLK_USB
                              |RCC_PERIPHCLK_RNG|RCC_PERIPHCLK_ADC12
                              |RCC_PERIPHCLK_FDCAN;
  PeriphClkInit.I2c1ClockSelection = RCC_I2C1CLKSOURCE_PCLK1;
  PeriphClkInit.I2c2ClockSelection = RCC_I2C2CLKSOURCE_PCLK1;
  PeriphClkInit.I2c3ClockSelection = RCC_I2C3CLKSOURCE_PCLK1;
  PeriphClkInit.I2c4ClockSelection = RCC_I2C4CLKSOURCE_PCLK1;
  PeriphClkInit.FdcanClockSelection = RCC_FDCANCLKSOURCE_PCLK1;
  PeriphClkInit.RngClockSelection = RCC_RNGCLKSOURCE_HSI48;
  PeriphClkInit.UsbClockSelection = RCC_USBCLKSOURCE_HSI48;
  PeriphClkInit.Adc12ClockSelection = RCC_ADC12CLKSOURCE_SYSCLK;
  PeriphClkInit.RTCClockSelection = RCC_RTCCLKSOURCE_LSE;
  if (HAL_RCCEx_PeriphCLKConfig(&PeriphClkInit) != HAL_OK)
  {
    Error_Handler();
  }
}

void Error_Handler(void)
{
  __disable_irq();
  while (1)
  {
  }
}

/************************ (C) COPYRIGHT STMicroelectronics *****END OF FILE****/
